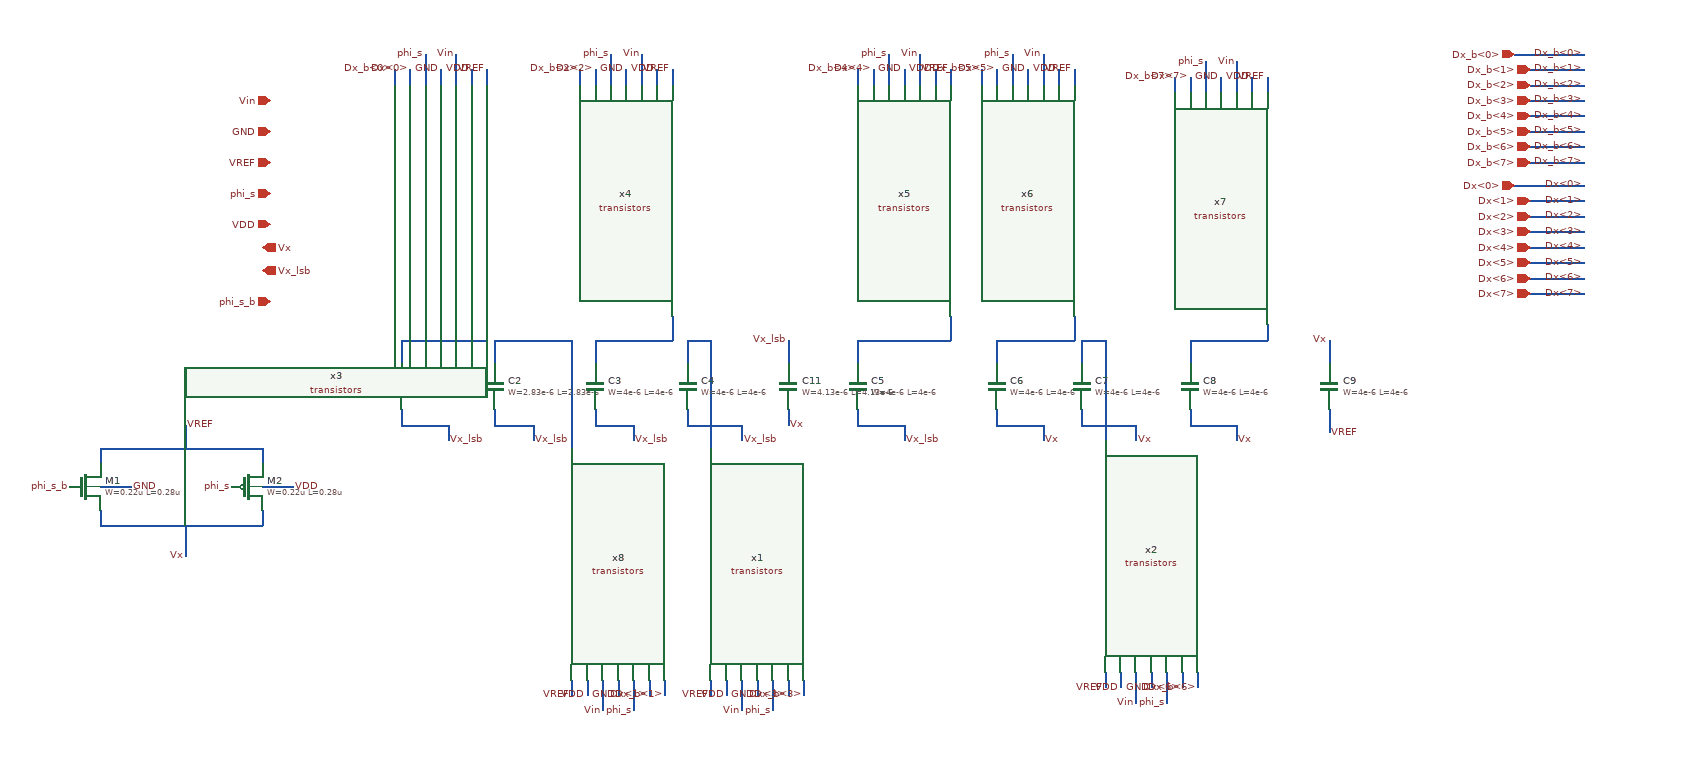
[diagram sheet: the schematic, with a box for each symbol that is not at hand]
v {xschem version=3.4.8RC file_version=1.3}
G {}
K {}
V {}
S {}
F {}
E {}
N -220 -110 -220 -90 {lab=Vx_lsb}
N -100 -110 -100 -90 {lab=Vx_lsb}
N 30 -110 30 -90 {lab=Vx_lsb}
N 150 -110 150 -90 {lab=Vx_lsb}
N 370 -110 370 -90 {lab=Vx_lsb}
N 800 -110 800 -90 {lab=Vx}
N 660 -110 660 -90 {lab=Vx}
N 550 -110 550 -90 {lab=Vx}
N 280 -110 280 -90 {lab=Vx}
N -100 -200 -100 -170 {lab=#net1}
N -220 -200 -220 -170 {lab=#net2}
N 30 -200 30 -170 {lab=#net3}
N 150 -200 150 -170 {lab=#net4}
N 370 -200 370 -170 {lab=#net5}
N 550 -200 550 -170 {lab=#net6}
N 660 -200 660 -170 {lab=#net7}
N 800 -200 800 -170 {lab=#net8}
N -110 -230 -110 -200 {lab=#net2}
N -0 -200 0 -60 {lab=#net1}
N 180 -200 180 -70 {lab=#net4}
N 180 -70 180 -60 {lab=#net4}
N 130 -230 130 -200 {lab=#net3}
N 490 -230 490 -200 {lab=#net5}
N 650 -230 650 -200 {lab=#net6}
N 900 -220 900 -200 {lab=#net8}
N 690 -200 690 -70 {lab=#net7}
N -230 -550 -230 -530 {lab=Dx_b<0>}
N -210 -550 -210 -530 {lab=Dx<0>}
N -190 -550 -190 -530 {lab=phi_s}
N -170 -550 -170 -530 {lab=GND}
N -150 -550 -150 -530 {lab=Vin}
N -130 -550 -130 -530 {lab=VDD}
N -110 -550 -110 -530 {lab=VREF}
N -190 -570 -190 -550 {lab=phi_s}
N -150 -570 -150 -550 {lab=Vin}
N 120 240 120 260 {lab=Dx_b<1>}
N 100 240 100 260 {lab=Dx<1>}
N 80 240 80 260 {lab=phi_s}
N 60 240 60 260 {lab=GND}
N 40 240 40 260 {lab=Vin}
N 20 240 20 260 {lab=VDD}
N 0 240 0 260 {lab=VREF}
N 80 260 80 280 {lab=phi_s}
N 40 260 40 280 {lab=Vin}
N 860 -90 860 -70 {lab=Vx}
N 730 -90 730 -80 {lab=Vx}
N 730 -80 730 -70 {lab=Vx}
N 610 -90 610 -70 {lab=Vx}
N 430 -90 430 -70 {lab=Vx_lsb}
N 220 -90 220 -70 {lab=Vx_lsb}
N -50 -90 -50 -70 {lab=Vx_lsb}
N 80 -90 80 -70 {lab=Vx_lsb}
N -160 -90 -160 -70 {lab=Vx_lsb}
N -220 -90 -160 -90 {lab=Vx_lsb}
N -100 -90 -50 -90 {lab=Vx_lsb}
N 30 -90 80 -90 {lab=Vx_lsb}
N 150 -90 220 -90 {lab=Vx_lsb}
N 370 -90 430 -90 {lab=Vx_lsb}
N 800 -90 860 -90 {lab=Vx}
N 660 -90 730 -90 {lab=Vx}
N 550 -90 610 -90 {lab=Vx}
N 1220 -570 1310 -570 {lab=Dx_b<0>}
N 1240 -550 1310 -550 {lab=Dx_b<1>}
N 1240 -530 1310 -530 {lab=Dx_b<2>}
N 1240 -510 1310 -510 {lab=Dx_b<3>}
N 1240 -490 1310 -490 {lab=Dx_b<4>}
N 1240 -470 1310 -470 {lab=Dx_b<5>}
N 1240 -450 1310 -450 {lab=Dx_b<6>}
N 1240 -430 1310 -430 {lab=Dx_b<7>}
N 1220 -400 1310 -400 {lab=Dx<0>}
N 1240 -380 1310 -380 {lab=Dx<1>}
N 1240 -360 1310 -360 {lab=Dx<2>}
N 1240 -340 1310 -340 {lab=Dx<3>}
N 1240 -320 1310 -320 {lab=Dx<4>}
N 1240 -300 1310 -300 {lab=Dx<5>}
N 1240 -280 1310 -280 {lab=Dx<6>}
N 1240 -260 1310 -260 {lab=Dx<7>}
N -100 -200 0 -200 {lab=#net1}
N -220 -200 -110 -200 {lab=#net2}
N 30 -200 130 -200 {lab=#net3}
N 150 -200 180 -200 {lab=#net4}
N 370 -200 490 -200 {lab=#net5}
N 550 -200 650 -200 {lab=#net6}
N 660 -200 690 -200 {lab=#net7}
N 800 -200 900 -200 {lab=#net8}
N 280 -200 280 -170 {lab=Vx_lsb}
N 980 -110 980 -80 {lab=VREF}
N 980 -200 980 -170 {lab=Vx}
N 10 -550 10 -530 {lab=Dx_b<2>}
N 30 -550 30 -530 {lab=Dx<2>}
N 50 -550 50 -530 {lab=phi_s}
N 70 -550 70 -530 {lab=GND}
N 90 -550 90 -530 {lab=Vin}
N 110 -550 110 -530 {lab=VDD}
N 130 -550 130 -530 {lab=VREF}
N 50 -570 50 -550 {lab=phi_s}
N 90 -570 90 -550 {lab=Vin}
N 370 -550 370 -530 {lab=Dx_b<4>}
N 390 -550 390 -530 {lab=Dx<4>}
N 410 -550 410 -530 {lab=phi_s}
N 430 -550 430 -530 {lab=GND}
N 450 -550 450 -530 {lab=Vin}
N 470 -550 470 -530 {lab=VDD}
N 490 -550 490 -530 {lab=VREF}
N 410 -570 410 -550 {lab=phi_s}
N 450 -570 450 -550 {lab=Vin}
N 530 -550 530 -530 {lab=Dx_b<5>}
N 550 -550 550 -530 {lab=Dx<5>}
N 570 -550 570 -530 {lab=phi_s}
N 590 -550 590 -530 {lab=GND}
N 610 -550 610 -530 {lab=Vin}
N 630 -550 630 -530 {lab=VDD}
N 650 -550 650 -530 {lab=VREF}
N 570 -570 570 -550 {lab=phi_s}
N 610 -570 610 -550 {lab=Vin}
N 780 -540 780 -520 {lab=Dx_b<7>}
N 800 -540 800 -520 {lab=Dx<7>}
N 820 -540 820 -520 {lab=phi_s}
N 840 -540 840 -520 {lab=GND}
N 860 -540 860 -520 {lab=Vin}
N 880 -540 880 -520 {lab=VDD}
N 900 -540 900 -520 {lab=VREF}
N 820 -560 820 -540 {lab=phi_s}
N 860 -560 860 -540 {lab=Vin}
N 300 240 300 260 {lab=Dx_b<3>}
N 280 240 280 260 {lab=Dx<3>}
N 260 240 260 260 {lab=phi_s}
N 240 240 240 260 {lab=GND}
N 220 240 220 260 {lab=Vin}
N 200 240 200 260 {lab=VDD}
N 180 240 180 260 {lab=VREF}
N 260 260 260 280 {lab=phi_s}
N 220 260 220 280 {lab=Vin}
N 810 230 810 250 {lab=Dx_b<6>}
N 790 230 790 250 {lab=Dx<6>}
N 770 230 770 250 {lab=phi_s}
N 750 230 750 250 {lab=GND}
N 730 230 730 250 {lab=Vin}
N 710 230 710 250 {lab=VDD}
N 690 230 690 250 {lab=VREF}
N 770 250 770 270 {lab=phi_s}
N 730 250 730 270 {lab=Vin}
N -610 -60 -610 -40 {lab=VREF}
N -610 -60 -400 -60 {lab=VREF}
N -400 -60 -400 -40 {lab=VREF}
N -500 -90 -500 -60 {lab=VREF}
N -610 -10 -570 -10 {lab=GND}
N -610 20 -610 40 {lab=Vx}
N -610 40 -400 40 {lab=Vx}
N -400 20 -400 40 {lab=Vx}
N -500 40 -500 80 {lab=Vx}
N -400 -10 -360 -10 {lab=VDD}
C {symbols/cap_mim_2f0fF.sym} -220 -140 0 0 {name=C1
W=2e-6
L=2e-6
model=cap_mim_2f0fF
spiceprefix=X
m=1}
C {symbols/cap_mim_2f0fF.sym} -100 -140 0 0 {name=C2
W=2.83e-6
L=2.83e-6
model=cap_mim_2f0fF
spiceprefix=X
m=1}
C {symbols/cap_mim_2f0fF.sym} 30 -140 0 0 {name=C3
W=4e-6
L=4e-6
model=cap_mim_2f0fF
spiceprefix=X
m=1}
C {symbols/cap_mim_2f0fF.sym} 150 -140 0 0 {name=C4
W=4e-6
L=4e-6
model=cap_mim_2f0fF
spiceprefix=X
m=2}
C {symbols/cap_mim_2f0fF.sym} 370 -140 0 0 {name=C5
W=4e-6
L=4e-6
model=cap_mim_2f0fF
spiceprefix=X
m=4}
C {symbols/cap_mim_2f0fF.sym} 550 -140 0 0 {name=C6
W=4e-6
L=4e-6
model=cap_mim_2f0fF
spiceprefix=X
m=1}
C {symbols/cap_mim_2f0fF.sym} 660 -140 0 0 {name=C7
W=4e-6
L=4e-6
model=cap_mim_2f0fF
spiceprefix=X
m=2}
C {symbols/cap_mim_2f0fF.sym} 800 -140 0 0 {name=C8
W=4e-6
L=4e-6
model=cap_mim_2f0fF
spiceprefix=X
m=4}
C {symbols/cap_mim_2f0fF.sym} 280 -140 0 0 {name=C11
W=4.13e-6
L=4.13e-6
model=cap_mim_2f0fF
spiceprefix=X
m=1}
C {ipin.sym} -390 -510 0 0 {name=p1 lab=Vin}
C {ipin.sym} -390 -470 0 0 {name=p2 lab=GND}
C {ipin.sym} -390 -430 0 0 {name=p3 lab=VREF}
C {opin.sym} -400 -320 0 0 {name=p4 lab=Vx}
C {ipin.sym} -390 -390 0 0 {name=p5 lab=phi_s}
C {ipin.sym} -390 -350 0 0 {name=p6 lab=VDD}
C {ipin.sym} 1220 -570 0 0 {name=p7 lab=Dx_b<0>}
C {ipin.sym} 1220 -400 0 0 {name=p8 lab=Dx<0>}
C {lab_wire.sym} -170 -550 1 0 {name=p9 sig_type=std_logic lab=GND}
C {lab_wire.sym} -150 -570 1 0 {name=p11 sig_type=std_logic lab=Vin}
C {lab_wire.sym} -130 -550 1 0 {name=p12 sig_type=std_logic lab=VDD}
C {lab_wire.sym} -110 -550 1 0 {name=p13 sig_type=std_logic lab=VREF}
C {lab_wire.sym} -190 -570 1 0 {name=p14 sig_type=std_logic lab=phi_s}
C {lab_wire.sym} -230 -550 1 0 {name=p15 sig_type=std_logic lab=Dx_b<0>}
C {lab_wire.sym} -210 -550 1 0 {name=p16 sig_type=std_logic lab=Dx<0>}
C {lab_wire.sym} 60 260 3 0 {name=p45 sig_type=std_logic lab=GND}
C {lab_wire.sym} 40 280 3 0 {name=p46 sig_type=std_logic lab=Vin}
C {lab_wire.sym} 20 260 3 0 {name=p47 sig_type=std_logic lab=VDD}
C {lab_wire.sym} 0 260 3 0 {name=p48 sig_type=std_logic lab=VREF}
C {lab_wire.sym} 80 280 3 0 {name=p49 sig_type=std_logic lab=phi_s}
C {lab_wire.sym} 120 260 3 0 {name=p50 sig_type=std_logic lab=Dx_b<1>}
C {lab_wire.sym} 100 260 3 0 {name=p51 sig_type=std_logic lab=Dx<1>}
C {lab_wire.sym} 860 -70 2 0 {name=p80 sig_type=std_logic lab=Vx}
C {lab_wire.sym} 730 -70 2 0 {name=p81 sig_type=std_logic lab=Vx}
C {lab_wire.sym} 610 -70 2 0 {name=p83 sig_type=std_logic lab=Vx}
C {lab_wire.sym} 280 -90 2 0 {name=p84 sig_type=std_logic lab=Vx}
C {lab_wire.sym} 430 -70 2 0 {name=p85 sig_type=std_logic lab=Vx_lsb}
C {lab_wire.sym} 220 -70 2 0 {name=p86 sig_type=std_logic lab=Vx_lsb}
C {lab_wire.sym} 80 -70 2 0 {name=p87 sig_type=std_logic lab=Vx_lsb}
C {lab_wire.sym} -50 -70 2 0 {name=p88 sig_type=std_logic lab=Vx_lsb}
C {lab_wire.sym} -160 -70 2 0 {name=p89 sig_type=std_logic lab=Vx_lsb}
C {lab_wire.sym} 1310 -570 0 0 {name=p90 sig_type=std_logic lab=Dx_b<0>}
C {lab_wire.sym} 1310 -550 0 0 {name=p91 sig_type=std_logic lab=Dx_b<1>}
C {lab_wire.sym} 1310 -530 0 0 {name=p92 sig_type=std_logic lab=Dx_b<2>}
C {lab_wire.sym} 1310 -510 0 0 {name=p93 sig_type=std_logic lab=Dx_b<3>}
C {lab_wire.sym} 1310 -490 0 0 {name=p94 sig_type=std_logic lab=Dx_b<4>}
C {lab_wire.sym} 1310 -470 0 0 {name=p95 sig_type=std_logic lab=Dx_b<5>}
C {lab_wire.sym} 1310 -450 0 0 {name=p96 sig_type=std_logic lab=Dx_b<6>}
C {lab_wire.sym} 1310 -430 0 0 {name=p97 sig_type=std_logic lab=Dx_b<7>}
C {lab_wire.sym} 1310 -400 0 0 {name=p100 sig_type=std_logic lab=Dx<0>}
C {lab_wire.sym} 1310 -380 0 0 {name=p101 sig_type=std_logic lab=Dx<1>}
C {lab_wire.sym} 1310 -360 0 0 {name=p102 sig_type=std_logic lab=Dx<2>}
C {lab_wire.sym} 1310 -340 0 0 {name=p103 sig_type=std_logic lab=Dx<3>}
C {lab_wire.sym} 1310 -320 0 0 {name=p104 sig_type=std_logic lab=Dx<4>}
C {lab_wire.sym} 1310 -300 0 0 {name=p105 sig_type=std_logic lab=Dx<5>}
C {lab_wire.sym} 1310 -280 0 0 {name=p106 sig_type=std_logic lab=Dx<6>}
C {lab_wire.sym} 1310 -260 0 0 {name=p107 sig_type=std_logic lab=Dx<7>}
C {ipin.sym} 1240 -550 0 0 {name=p110 lab=Dx_b<1>}
C {ipin.sym} 1240 -530 0 0 {name=p111 lab=Dx_b<2>}
C {ipin.sym} 1240 -510 0 0 {name=p112 lab=Dx_b<3>}
C {ipin.sym} 1240 -490 0 0 {name=p113 lab=Dx_b<4>}
C {ipin.sym} 1240 -470 0 0 {name=p114 lab=Dx_b<5>}
C {ipin.sym} 1240 -450 0 0 {name=p115 lab=Dx_b<6>}
C {ipin.sym} 1240 -430 0 0 {name=p116 lab=Dx_b<7>}
C {ipin.sym} 1240 -380 0 0 {name=p119 lab=Dx<1>}
C {ipin.sym} 1240 -360 0 0 {name=p120 lab=Dx<2>}
C {ipin.sym} 1240 -340 0 0 {name=p121 lab=Dx<3>}
C {ipin.sym} 1240 -320 0 0 {name=p122 lab=Dx<4>}
C {ipin.sym} 1240 -300 0 0 {name=p123 lab=Dx<5>}
C {ipin.sym} 1240 -280 0 0 {name=p124 lab=Dx<6>}
C {ipin.sym} 1240 -260 0 0 {name=p125 lab=Dx<7>}
C {lab_wire.sym} 280 -200 0 0 {name=p59 sig_type=std_logic lab=Vx_lsb}
C {opin.sym} -400 -290 0 0 {name=p60 lab=Vx_lsb}
C {symbols/cap_mim_2f0fF.sym} 980 -140 0 0 {name=C9
W=4e-6
L=4e-6
model=cap_mim_2f0fF
spiceprefix=X
m=1}
C {lab_wire.sym} 980 -80 2 0 {name=p10 sig_type=std_logic lab=VREF}
C {lab_wire.sym} 980 -200 0 0 {name=p61 sig_type=std_logic lab=Vx}
C {lab_wire.sym} 70 -550 1 0 {name=p17 sig_type=std_logic lab=GND}
C {lab_wire.sym} 90 -570 1 0 {name=p18 sig_type=std_logic lab=Vin}
C {lab_wire.sym} 110 -550 1 0 {name=p19 sig_type=std_logic lab=VDD}
C {lab_wire.sym} 130 -550 1 0 {name=p20 sig_type=std_logic lab=VREF}
C {lab_wire.sym} 50 -570 1 0 {name=p21 sig_type=std_logic lab=phi_s}
C {lab_wire.sym} 10 -550 1 0 {name=p22 sig_type=std_logic lab=Dx_b<2>}
C {lab_wire.sym} 30 -550 1 0 {name=p23 sig_type=std_logic lab=Dx<2>}
C {lab_wire.sym} 430 -550 1 0 {name=p24 sig_type=std_logic lab=GND}
C {lab_wire.sym} 450 -570 1 0 {name=p25 sig_type=std_logic lab=Vin}
C {lab_wire.sym} 470 -550 1 0 {name=p26 sig_type=std_logic lab=VDD}
C {lab_wire.sym} 490 -550 1 0 {name=p27 sig_type=std_logic lab=VREF}
C {lab_wire.sym} 410 -570 1 0 {name=p28 sig_type=std_logic lab=phi_s}
C {lab_wire.sym} 370 -550 1 0 {name=p29 sig_type=std_logic lab=Dx_b<4>}
C {lab_wire.sym} 390 -550 1 0 {name=p30 sig_type=std_logic lab=Dx<4>}
C {lab_wire.sym} 590 -550 1 0 {name=p31 sig_type=std_logic lab=GND}
C {lab_wire.sym} 610 -570 1 0 {name=p32 sig_type=std_logic lab=Vin}
C {lab_wire.sym} 630 -550 1 0 {name=p33 sig_type=std_logic lab=VDD}
C {lab_wire.sym} 650 -550 1 0 {name=p34 sig_type=std_logic lab=VREF}
C {lab_wire.sym} 570 -570 1 0 {name=p35 sig_type=std_logic lab=phi_s}
C {lab_wire.sym} 530 -550 1 0 {name=p36 sig_type=std_logic lab=Dx_b<5>}
C {lab_wire.sym} 550 -550 1 0 {name=p37 sig_type=std_logic lab=Dx<5>}
C {lab_wire.sym} 840 -540 1 0 {name=p38 sig_type=std_logic lab=GND}
C {lab_wire.sym} 860 -560 1 0 {name=p39 sig_type=std_logic lab=Vin}
C {lab_wire.sym} 880 -540 1 0 {name=p40 sig_type=std_logic lab=VDD}
C {lab_wire.sym} 900 -540 1 0 {name=p41 sig_type=std_logic lab=VREF}
C {lab_wire.sym} 820 -560 1 0 {name=p42 sig_type=std_logic lab=phi_s}
C {lab_wire.sym} 780 -540 1 0 {name=p43 sig_type=std_logic lab=Dx_b<7>}
C {lab_wire.sym} 800 -540 1 0 {name=p44 sig_type=std_logic lab=Dx<7>}
C {lab_wire.sym} 240 260 3 0 {name=p52 sig_type=std_logic lab=GND}
C {lab_wire.sym} 220 280 3 0 {name=p53 sig_type=std_logic lab=Vin}
C {lab_wire.sym} 200 260 3 0 {name=p54 sig_type=std_logic lab=VDD}
C {lab_wire.sym} 180 260 3 0 {name=p55 sig_type=std_logic lab=VREF}
C {lab_wire.sym} 260 280 3 0 {name=p56 sig_type=std_logic lab=phi_s}
C {lab_wire.sym} 300 260 3 0 {name=p57 sig_type=std_logic lab=Dx_b<3>}
C {lab_wire.sym} 280 260 3 0 {name=p58 sig_type=std_logic lab=Dx<3>}
C {lab_wire.sym} 750 250 3 0 {name=p62 sig_type=std_logic lab=GND}
C {lab_wire.sym} 730 270 3 0 {name=p63 sig_type=std_logic lab=Vin}
C {lab_wire.sym} 710 250 3 0 {name=p64 sig_type=std_logic lab=VDD}
C {lab_wire.sym} 690 250 3 0 {name=p65 sig_type=std_logic lab=VREF}
C {lab_wire.sym} 770 270 3 0 {name=p66 sig_type=std_logic lab=phi_s}
C {lab_wire.sym} 810 250 3 0 {name=p67 sig_type=std_logic lab=Dx_b<6>}
C {lab_wire.sym} 790 250 3 0 {name=p68 sig_type=std_logic lab=Dx<6>}
C {symbols/nfet_03v3.sym} -630 -10 0 0 {name=M1
L=0.28u
W=0.22u
nf=1
m=1
ad="'int((nf+1)/2) * W/nf * 0.18u'"
pd="'2*int((nf+1)/2) * (W/nf + 0.18u)'"
as="'int((nf+2)/2) * W/nf * 0.18u'"
ps="'2*int((nf+2)/2) * (W/nf + 0.18u)'"
nrd="'0.18u / W'" nrs="'0.18u / W'"
sa=0 sb=0 sd=0
model=nfet_03v3
spiceprefix=X
}
C {symbols/pfet_03v3.sym} -420 -10 0 0 {name=M2
L=0.28u
W=0.22u
nf=1
m=1
ad="'int((nf+1)/2) * W/nf * 0.18u'"
pd="'2*int((nf+1)/2) * (W/nf + 0.18u)'"
as="'int((nf+2)/2) * W/nf * 0.18u'"
ps="'2*int((nf+2)/2) * (W/nf + 0.18u)'"
nrd="'0.18u / W'" nrs="'0.18u / W'"
sa=0 sb=0 sd=0
model=pfet_03v3
spiceprefix=X
}
C {lab_wire.sym} -500 -90 2 0 {name=p70 sig_type=std_logic lab=VREF}
C {lab_wire.sym} -500 80 0 0 {name=p69 sig_type=std_logic lab=Vx}
C {lab_wire.sym} -360 -10 2 0 {name=p71 sig_type=std_logic lab=VDD}
C {lab_wire.sym} -570 -10 2 0 {name=p72 sig_type=std_logic lab=GND}
C {lab_wire.sym} -440 -10 0 0 {name=p73 sig_type=std_logic lab=phi_s}
C {lab_wire.sym} -650 -10 0 0 {name=p74 sig_type=std_logic lab=phi_s_b}
C {ipin.sym} -390 -250 0 0 {name=p75 lab=phi_s_b}
C {transistors.sym} 60 90 3 0 {name=x8}
C {transistors.sym} 240 90 3 0 {name=x1}
C {transistors.sym} 750 80 3 0 {name=x2}
C {transistors.sym} -170 -380 1 0 {name=x3}
C {transistors.sym} 70 -380 1 0 {name=x4}
C {transistors.sym} 430 -380 1 0 {name=x5}
C {transistors.sym} 590 -380 1 0 {name=x6}
C {transistors.sym} 840 -370 1 0 {name=x7}
